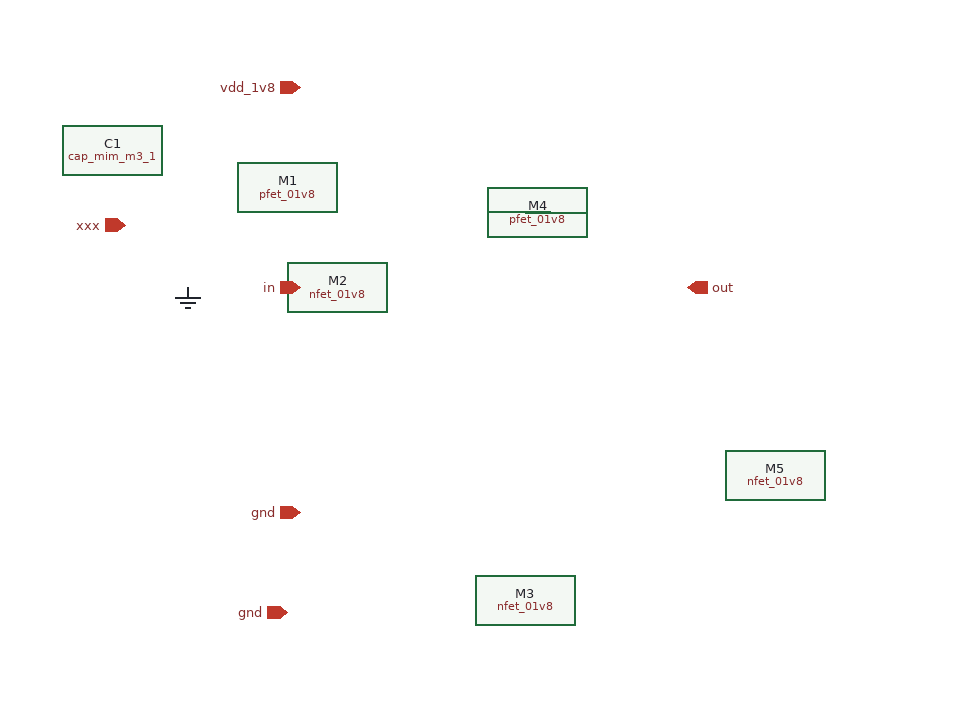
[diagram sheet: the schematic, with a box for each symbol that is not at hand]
v {xschem version=3.0.0 file_version=1.2 }
G {}
K {}
V {}
S {}
E {}
N 250 -10 270 -10 { lab=#net1}
C {devices/gnd.sym} -20 50 0 0 {name=l1 lab=GND}
C {devices/iopin.sym} -70 0 0 0 {name=p1 lab=xxx}
C {nfet_01v8.sym} 100 50 0 0 {name=M2
L=0.15
W=1
nf=1 
mult=1
ad="'int((nf+1)/2) * W/nf * 0.29'" 
pd="'2*int((nf+1)/2) * (W/nf + 0.29)'"
as="'int((nf+2)/2) * W/nf * 0.29'" 
ps="'2*int((nf+2)/2) * (W/nf + 0.29)'"
nrd="'0.29 / W'" nrs="'0.29 / W'"
sa=0 sb=0 sd=0
model=nfet_01v8
spiceprefix=X
}
C {pfet_01v8.sym} 60 -30 0 0 {name=M1
L=0.15
W=1
nf=1
mult=1
ad="'int((nf+1)/2) * W/nf * 0.29'" 
pd="'2*int((nf+1)/2) * (W/nf + 0.29)'"
as="'int((nf+2)/2) * W/nf * 0.29'" 
ps="'2*int((nf+2)/2) * (W/nf + 0.29)'"
nrd="'0.29 / W'" nrs="'0.29 / W'"
sa=0 sb=0 sd=0
model=pfet_01v8
spiceprefix=X
}
C {cap_mim_m3_1.sym} -80 -60 0 0 {name=C1 model=cap_mim_m3_1 W=1 L=1 MF=1 spiceprefix=X}
C {nfet_01v8.sym} 250 300 0 0 {name=M3
L=0.15
W=1
nf=1 
mult=1
ad="'int((nf+1)/2) * W/nf * 0.29'" 
pd="'2*int((nf+1)/2) * (W/nf + 0.29)'"
as="'int((nf+2)/2) * W/nf * 0.29'" 
ps="'2*int((nf+2)/2) * (W/nf + 0.29)'"
nrd="'0.29 / W'" nrs="'0.29 / W'"
sa=0 sb=0 sd=0
model=nfet_01v8
spiceprefix=X
}
C {pfet_01v8.sym} 230 -10 0 0 {name=M4
L=0.15
W=1
nf=1
mult=1
ad="'int((nf+1)/2) * W/nf * 0.29'" 
pd="'2*int((nf+1)/2) * (W/nf + 0.29)'"
as="'int((nf+2)/2) * W/nf * 0.29'" 
ps="'2*int((nf+2)/2) * (W/nf + 0.29)'"
nrd="'0.29 / W'" nrs="'0.29 / W'"
sa=0 sb=0 sd=0
model=pfet_01v8
spiceprefix=X
}
C {devices/ipin.sym} 70 -110 0 0 {name=p2 lab=vdd_1v8}
C {devices/ipin.sym} 70 230 0 0 {name=p3 lab=gnd}
C {devices/ipin.sym} 70 50 0 0 {name=p4 lab=in}
C {devices/opin.sym} 380 50 0 0 {name=p5 lab=out}
C {devices/ipin.sym} 60 310 0 0 {name=p6 lab=gnd}
C {nfet_01v8.sym} 450 200 0 0 {name=M5
L=0.15
W=1
nf=1 
mult=1
ad="'int((nf+1)/2) * W/nf * 0.29'" 
pd="'2*int((nf+1)/2) * (W/nf + 0.29)'"
as="'int((nf+2)/2) * W/nf * 0.29'" 
ps="'2*int((nf+2)/2) * (W/nf + 0.29)'"
nrd="'0.29 / W'" nrs="'0.29 / W'"
sa=0 sb=0 sd=0
model=nfet_01v8
spiceprefix=X
}
